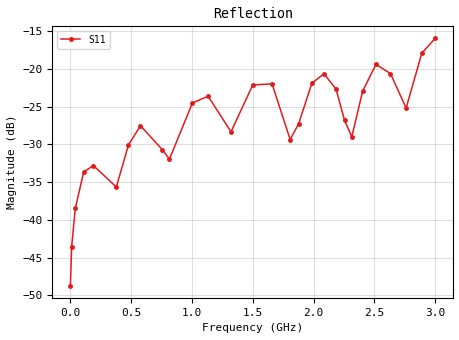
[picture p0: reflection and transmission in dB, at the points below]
# HZ S RI R 50
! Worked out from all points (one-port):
!   303 points, 100 kHz to 3 GHz, reference 50 ohm
!   lowest |S11| = -48.7 dB at 100 kHz (marker M1), VSWR 1.01, Z = 50.3 - j0.165 ohm
!   |S11| at or under -10 dB: start of sweep to end of sweep
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100000  0.00327 -0.00164
1.003344e7  0.00578 0.00316
3.983377e7  0.00966 0.00692
1.093679e8  0.0197 0.00653
1.888354e8  0.0228 -0.00187
3.775708e8  0.0163 0.00243
4.769053e8  0.0307 0.00555
5.762397e8  0.0407 -0.0103
7.550417e8  0.0205 -0.0208
8.146423e8  0.0218 -0.0127
1.003378e9  0.0517 -0.0291
1.132513e9  0.0316 -0.0578
1.321248e9  0.0143 -0.0355
1.50005e9  0.0297 -0.0724
1.658985e9  -0.0282 -0.0743
1.807987e9  -0.0127 -0.0315
1.877521e9  0.00788 -0.0426
1.986789e9  0.00117 -0.0803
2.086123e9  -0.0386 -0.0844
2.185457e9  -0.0557 -0.0476
2.254992e9  -0.0349 -0.0293
2.314592e9  -0.0117 -0.0335
2.403993e9  -0.000206 -0.0711
2.513261e9  -0.0397 -0.0994
2.632462e9  -0.0678 -0.0638
2.761597e9  -0.0192 -0.0515
2.890732e9  -0.021 -0.1253
3e9  -0.0882 -0.1325
